VERSION 5.7 ;
  NOWIREEXTENSIONATPIN ON ;
  DIVIDERCHAR "/" ;
  BUSBITCHARS "[]" ;
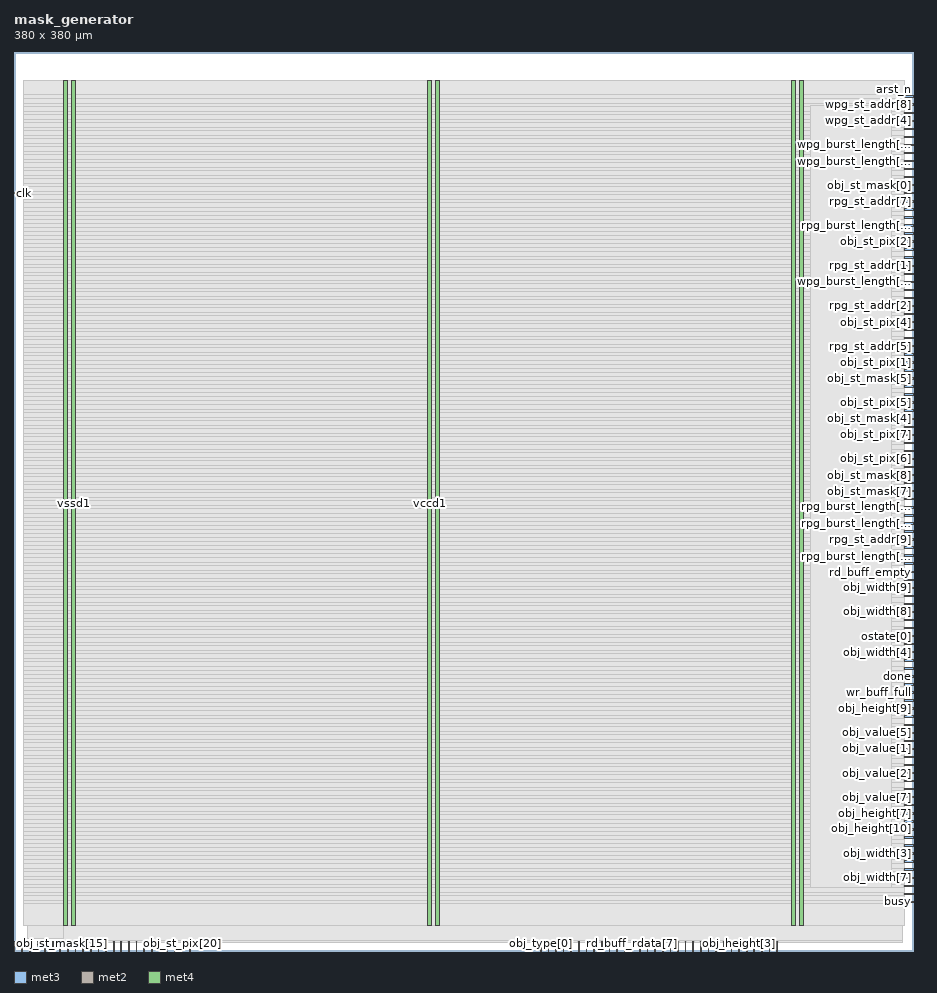
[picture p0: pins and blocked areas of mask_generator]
MACRO mask_generator
  CLASS BLOCK ;
  FOREIGN mask_generator ;
  ORIGIN 0.000 0.000 ;
  SIZE 380.000 BY 380.000 ;
  PIN arst_n
    DIRECTION INPUT ;
    USE SIGNAL ;
    ANTENNAGATEAREA 1.286700 ;
    ANTENNADIFFAREA 0.434700 ;
    PORT
      LAYER met3 ;
        RECT 376.000 360.440 380.000 361.040 ;
    END
  END arst_n
  PIN busy
    DIRECTION OUTPUT ;
    USE SIGNAL ;
    ANTENNADIFFAREA 0.340600 ;
    PORT
      LAYER met3 ;
        RECT 376.000 20.440 380.000 21.040 ;
    END
  END busy
  PIN clk
    DIRECTION INPUT ;
    USE SIGNAL ;
    ANTENNAGATEAREA 1.286700 ;
    ANTENNADIFFAREA 0.434700 ;
    PORT
      LAYER met3 ;
        RECT 0.000 319.640 4.000 320.240 ;
    END
  END clk
  PIN done
    DIRECTION OUTPUT ;
    USE SIGNAL ;
    ANTENNADIFFAREA 0.340600 ;
    PORT
      LAYER met3 ;
        RECT 376.000 115.640 380.000 116.240 ;
    END
  END done
  PIN obj_height[0]
    DIRECTION INPUT ;
    USE SIGNAL ;
    ANTENNAGATEAREA 0.631200 ;
    ANTENNADIFFAREA 0.434700 ;
    PORT
      LAYER met2 ;
        RECT 322.090 0.000 322.370 4.000 ;
    END
  END obj_height[0]
  PIN obj_height[10]
    DIRECTION INPUT ;
    USE SIGNAL ;
    ANTENNAGATEAREA 0.560700 ;
    ANTENNADIFFAREA 0.434700 ;
    PORT
      LAYER met3 ;
        RECT 376.000 54.440 380.000 55.040 ;
    END
  END obj_height[10]
  PIN obj_height[1]
    DIRECTION INPUT ;
    USE SIGNAL ;
    ANTENNAGATEAREA 0.631200 ;
    ANTENNADIFFAREA 0.434700 ;
    PORT
      LAYER met2 ;
        RECT 309.210 0.000 309.490 4.000 ;
    END
  END obj_height[1]
  PIN obj_height[2]
    DIRECTION INPUT ;
    USE SIGNAL ;
    ANTENNAGATEAREA 0.631200 ;
    ANTENNADIFFAREA 0.434700 ;
    PORT
      LAYER met2 ;
        RECT 302.770 0.000 303.050 4.000 ;
    END
  END obj_height[2]
  PIN obj_height[3]
    DIRECTION INPUT ;
    USE SIGNAL ;
    ANTENNAGATEAREA 0.631200 ;
    ANTENNADIFFAREA 0.434700 ;
    PORT
      LAYER met2 ;
        RECT 305.990 0.000 306.270 4.000 ;
    END
  END obj_height[3]
  PIN obj_height[4]
    DIRECTION INPUT ;
    USE SIGNAL ;
    ANTENNAGATEAREA 0.631200 ;
    ANTENNADIFFAREA 0.434700 ;
    PORT
      LAYER met2 ;
        RECT 312.430 0.000 312.710 4.000 ;
    END
  END obj_height[4]
  PIN obj_height[5]
    DIRECTION INPUT ;
    USE SIGNAL ;
    ANTENNAGATEAREA 0.631200 ;
    ANTENNADIFFAREA 0.434700 ;
    PORT
      LAYER met2 ;
        RECT 299.550 0.000 299.830 4.000 ;
    END
  END obj_height[5]
  PIN obj_height[6]
    DIRECTION INPUT ;
    USE SIGNAL ;
    ANTENNAGATEAREA 0.631200 ;
    ANTENNADIFFAREA 0.434700 ;
    PORT
      LAYER met2 ;
        RECT 296.330 0.000 296.610 4.000 ;
    END
  END obj_height[6]
  PIN obj_height[7]
    DIRECTION INPUT ;
    USE SIGNAL ;
    ANTENNAGATEAREA 0.631200 ;
    ANTENNADIFFAREA 0.434700 ;
    PORT
      LAYER met3 ;
        RECT 376.000 57.840 380.000 58.440 ;
    END
  END obj_height[7]
  PIN obj_height[8]
    DIRECTION INPUT ;
    USE SIGNAL ;
    ANTENNAGATEAREA 0.631200 ;
    ANTENNADIFFAREA 0.434700 ;
    PORT
      LAYER met3 ;
        RECT 376.000 61.240 380.000 61.840 ;
    END
  END obj_height[8]
  PIN obj_height[9]
    DIRECTION INPUT ;
    USE SIGNAL ;
    ANTENNAGATEAREA 0.631200 ;
    ANTENNADIFFAREA 0.434700 ;
    PORT
      LAYER met3 ;
        RECT 376.000 102.040 380.000 102.640 ;
    END
  END obj_height[9]
  PIN obj_st_mask[0]
    DIRECTION INPUT ;
    USE SIGNAL ;
    ANTENNAGATEAREA 0.560700 ;
    ANTENNADIFFAREA 0.434700 ;
    PORT
      LAYER met3 ;
        RECT 376.000 323.040 380.000 323.640 ;
    END
  END obj_st_mask[0]
  PIN obj_st_mask[10]
    DIRECTION INPUT ;
    USE SIGNAL ;
    PORT
      LAYER met2 ;
        RECT 0.090 0.000 0.370 4.000 ;
    END
  END obj_st_mask[10]
  PIN obj_st_mask[11]
    DIRECTION INPUT ;
    USE SIGNAL ;
    PORT
      LAYER met2 ;
        RECT 3.310 0.000 3.590 4.000 ;
    END
  END obj_st_mask[11]
  PIN obj_st_mask[12]
    DIRECTION INPUT ;
    USE SIGNAL ;
    PORT
      LAYER met2 ;
        RECT 6.530 0.000 6.810 4.000 ;
    END
  END obj_st_mask[12]
  PIN obj_st_mask[13]
    DIRECTION INPUT ;
    USE SIGNAL ;
    PORT
      LAYER met2 ;
        RECT 9.750 0.000 10.030 4.000 ;
    END
  END obj_st_mask[13]
  PIN obj_st_mask[14]
    DIRECTION INPUT ;
    USE SIGNAL ;
    PORT
      LAYER met2 ;
        RECT 12.970 0.000 13.250 4.000 ;
    END
  END obj_st_mask[14]
  PIN obj_st_mask[15]
    DIRECTION INPUT ;
    USE SIGNAL ;
    PORT
      LAYER met2 ;
        RECT 16.190 0.000 16.470 4.000 ;
    END
  END obj_st_mask[15]
  PIN obj_st_mask[16]
    DIRECTION INPUT ;
    USE SIGNAL ;
    PORT
      LAYER met2 ;
        RECT 19.410 0.000 19.690 4.000 ;
    END
  END obj_st_mask[16]
  PIN obj_st_mask[17]
    DIRECTION INPUT ;
    USE SIGNAL ;
    PORT
      LAYER met2 ;
        RECT 22.630 0.000 22.910 4.000 ;
    END
  END obj_st_mask[17]
  PIN obj_st_mask[18]
    DIRECTION INPUT ;
    USE SIGNAL ;
    PORT
      LAYER met2 ;
        RECT 25.850 0.000 26.130 4.000 ;
    END
  END obj_st_mask[18]
  PIN obj_st_mask[19]
    DIRECTION INPUT ;
    USE SIGNAL ;
    PORT
      LAYER met2 ;
        RECT 29.070 0.000 29.350 4.000 ;
    END
  END obj_st_mask[19]
  PIN obj_st_mask[1]
    DIRECTION INPUT ;
    USE SIGNAL ;
    ANTENNAGATEAREA 0.560700 ;
    ANTENNADIFFAREA 0.434700 ;
    PORT
      LAYER met3 ;
        RECT 376.000 312.840 380.000 313.440 ;
    END
  END obj_st_mask[1]
  PIN obj_st_mask[20]
    DIRECTION INPUT ;
    USE SIGNAL ;
    PORT
      LAYER met2 ;
        RECT 32.290 0.000 32.570 4.000 ;
    END
  END obj_st_mask[20]
  PIN obj_st_mask[21]
    DIRECTION INPUT ;
    USE SIGNAL ;
    PORT
      LAYER met2 ;
        RECT 35.510 0.000 35.790 4.000 ;
    END
  END obj_st_mask[21]
  PIN obj_st_mask[2]
    DIRECTION INPUT ;
    USE SIGNAL ;
    ANTENNAGATEAREA 0.560700 ;
    ANTENNADIFFAREA 0.434700 ;
    PORT
      LAYER met3 ;
        RECT 376.000 278.840 380.000 279.440 ;
    END
  END obj_st_mask[2]
  PIN obj_st_mask[3]
    DIRECTION INPUT ;
    USE SIGNAL ;
    ANTENNAGATEAREA 0.560700 ;
    ANTENNADIFFAREA 0.434700 ;
    PORT
      LAYER met3 ;
        RECT 376.000 302.640 380.000 303.240 ;
    END
  END obj_st_mask[3]
  PIN obj_st_mask[4]
    DIRECTION INPUT ;
    USE SIGNAL ;
    ANTENNAGATEAREA 0.560700 ;
    ANTENNADIFFAREA 0.434700 ;
    PORT
      LAYER met3 ;
        RECT 376.000 224.440 380.000 225.040 ;
    END
  END obj_st_mask[4]
  PIN obj_st_mask[5]
    DIRECTION INPUT ;
    USE SIGNAL ;
    ANTENNAGATEAREA 0.560700 ;
    ANTENNADIFFAREA 0.434700 ;
    PORT
      LAYER met3 ;
        RECT 376.000 241.440 380.000 242.040 ;
    END
  END obj_st_mask[5]
  PIN obj_st_mask[6]
    DIRECTION INPUT ;
    USE SIGNAL ;
    ANTENNAGATEAREA 0.560700 ;
    ANTENNADIFFAREA 0.434700 ;
    PORT
      LAYER met3 ;
        RECT 376.000 217.640 380.000 218.240 ;
    END
  END obj_st_mask[6]
  PIN obj_st_mask[7]
    DIRECTION INPUT ;
    USE SIGNAL ;
    ANTENNAGATEAREA 0.560700 ;
    ANTENNADIFFAREA 0.434700 ;
    PORT
      LAYER met3 ;
        RECT 376.000 193.840 380.000 194.440 ;
    END
  END obj_st_mask[7]
  PIN obj_st_mask[8]
    DIRECTION INPUT ;
    USE SIGNAL ;
    ANTENNAGATEAREA 0.560700 ;
    ANTENNADIFFAREA 0.434700 ;
    PORT
      LAYER met3 ;
        RECT 376.000 197.240 380.000 197.840 ;
    END
  END obj_st_mask[8]
  PIN obj_st_mask[9]
    DIRECTION INPUT ;
    USE SIGNAL ;
    ANTENNAGATEAREA 0.560700 ;
    ANTENNADIFFAREA 0.434700 ;
    PORT
      LAYER met3 ;
        RECT 376.000 183.640 380.000 184.240 ;
    END
  END obj_st_mask[9]
  PIN obj_st_pix[0]
    DIRECTION INPUT ;
    USE SIGNAL ;
    ANTENNAGATEAREA 0.560700 ;
    ANTENNADIFFAREA 0.434700 ;
    PORT
      LAYER met3 ;
        RECT 376.000 295.840 380.000 296.440 ;
    END
  END obj_st_pix[0]
  PIN obj_st_pix[10]
    DIRECTION INPUT ;
    USE SIGNAL ;
    PORT
      LAYER met2 ;
        RECT 38.730 0.000 39.010 4.000 ;
    END
  END obj_st_pix[10]
  PIN obj_st_pix[11]
    DIRECTION INPUT ;
    USE SIGNAL ;
    PORT
      LAYER met2 ;
        RECT 41.950 0.000 42.230 4.000 ;
    END
  END obj_st_pix[11]
  PIN obj_st_pix[12]
    DIRECTION INPUT ;
    USE SIGNAL ;
    PORT
      LAYER met2 ;
        RECT 45.170 0.000 45.450 4.000 ;
    END
  END obj_st_pix[12]
  PIN obj_st_pix[13]
    DIRECTION INPUT ;
    USE SIGNAL ;
    PORT
      LAYER met2 ;
        RECT 48.390 0.000 48.670 4.000 ;
    END
  END obj_st_pix[13]
  PIN obj_st_pix[14]
    DIRECTION INPUT ;
    USE SIGNAL ;
    PORT
      LAYER met2 ;
        RECT 51.610 0.000 51.890 4.000 ;
    END
  END obj_st_pix[14]
  PIN obj_st_pix[15]
    DIRECTION INPUT ;
    USE SIGNAL ;
    PORT
      LAYER met2 ;
        RECT 54.830 0.000 55.110 4.000 ;
    END
  END obj_st_pix[15]
  PIN obj_st_pix[16]
    DIRECTION INPUT ;
    USE SIGNAL ;
    PORT
      LAYER met2 ;
        RECT 58.050 0.000 58.330 4.000 ;
    END
  END obj_st_pix[16]
  PIN obj_st_pix[17]
    DIRECTION INPUT ;
    USE SIGNAL ;
    PORT
      LAYER met2 ;
        RECT 61.270 0.000 61.550 4.000 ;
    END
  END obj_st_pix[17]
  PIN obj_st_pix[18]
    DIRECTION INPUT ;
    USE SIGNAL ;
    PORT
      LAYER met2 ;
        RECT 64.490 0.000 64.770 4.000 ;
    END
  END obj_st_pix[18]
  PIN obj_st_pix[19]
    DIRECTION INPUT ;
    USE SIGNAL ;
    PORT
      LAYER met2 ;
        RECT 67.710 0.000 67.990 4.000 ;
    END
  END obj_st_pix[19]
  PIN obj_st_pix[1]
    DIRECTION INPUT ;
    USE SIGNAL ;
    ANTENNAGATEAREA 0.560700 ;
    ANTENNADIFFAREA 0.434700 ;
    PORT
      LAYER met3 ;
        RECT 376.000 248.240 380.000 248.840 ;
    END
  END obj_st_pix[1]
  PIN obj_st_pix[20]
    DIRECTION INPUT ;
    USE SIGNAL ;
    PORT
      LAYER met2 ;
        RECT 70.930 0.000 71.210 4.000 ;
    END
  END obj_st_pix[20]
  PIN obj_st_pix[21]
    DIRECTION INPUT ;
    USE SIGNAL ;
    PORT
      LAYER met2 ;
        RECT 74.150 0.000 74.430 4.000 ;
    END
  END obj_st_pix[21]
  PIN obj_st_pix[2]
    DIRECTION INPUT ;
    USE SIGNAL ;
    ANTENNAGATEAREA 0.560700 ;
    ANTENNADIFFAREA 0.434700 ;
    PORT
      LAYER met3 ;
        RECT 376.000 299.240 380.000 299.840 ;
    END
  END obj_st_pix[2]
  PIN obj_st_pix[3]
    DIRECTION INPUT ;
    USE SIGNAL ;
    ANTENNAGATEAREA 0.560700 ;
    ANTENNADIFFAREA 0.434700 ;
    PORT
      LAYER met3 ;
        RECT 376.000 244.840 380.000 245.440 ;
    END
  END obj_st_pix[3]
  PIN obj_st_pix[4]
    DIRECTION INPUT ;
    USE SIGNAL ;
    ANTENNAGATEAREA 0.560700 ;
    ANTENNADIFFAREA 0.434700 ;
    PORT
      LAYER met3 ;
        RECT 376.000 265.240 380.000 265.840 ;
    END
  END obj_st_pix[4]
  PIN obj_st_pix[5]
    DIRECTION INPUT ;
    USE SIGNAL ;
    ANTENNAGATEAREA 0.560700 ;
    ANTENNADIFFAREA 0.434700 ;
    PORT
      LAYER met3 ;
        RECT 376.000 231.240 380.000 231.840 ;
    END
  END obj_st_pix[5]
  PIN obj_st_pix[6]
    DIRECTION INPUT ;
    USE SIGNAL ;
    ANTENNAGATEAREA 0.560700 ;
    ANTENNADIFFAREA 0.434700 ;
    PORT
      LAYER met3 ;
        RECT 376.000 207.440 380.000 208.040 ;
    END
  END obj_st_pix[6]
  PIN obj_st_pix[7]
    DIRECTION INPUT ;
    USE SIGNAL ;
    ANTENNAGATEAREA 0.560700 ;
    ANTENNADIFFAREA 0.434700 ;
    PORT
      LAYER met3 ;
        RECT 376.000 221.040 380.000 221.640 ;
    END
  END obj_st_pix[7]
  PIN obj_st_pix[8]
    DIRECTION INPUT ;
    USE SIGNAL ;
    ANTENNAGATEAREA 0.560700 ;
    ANTENNADIFFAREA 0.434700 ;
    PORT
      LAYER met3 ;
        RECT 376.000 200.640 380.000 201.240 ;
    END
  END obj_st_pix[8]
  PIN obj_st_pix[9]
    DIRECTION INPUT ;
    USE SIGNAL ;
    ANTENNAGATEAREA 0.647700 ;
    ANTENNADIFFAREA 0.434700 ;
    PORT
      LAYER met3 ;
        RECT 376.000 23.840 380.000 24.440 ;
    END
  END obj_st_pix[9]
  PIN obj_type[0]
    DIRECTION INPUT ;
    USE SIGNAL ;
    ANTENNAGATEAREA 0.631200 ;
    ANTENNADIFFAREA 0.434700 ;
    PORT
      LAYER met2 ;
        RECT 222.270 0.000 222.550 4.000 ;
    END
  END obj_type[0]
  PIN obj_type[1]
    DIRECTION INPUT ;
    USE SIGNAL ;
    ANTENNAGATEAREA 0.631200 ;
    ANTENNADIFFAREA 0.434700 ;
    PORT
      LAYER met2 ;
        RECT 225.490 0.000 225.770 4.000 ;
    END
  END obj_type[1]
  PIN obj_type[2]
    DIRECTION INPUT ;
    USE SIGNAL ;
    ANTENNAGATEAREA 0.631200 ;
    ANTENNADIFFAREA 0.434700 ;
    PORT
      LAYER met2 ;
        RECT 254.470 0.000 254.750 4.000 ;
    END
  END obj_type[2]
  PIN obj_type[3]
    DIRECTION INPUT ;
    USE SIGNAL ;
    ANTENNAGATEAREA 0.631200 ;
    ANTENNADIFFAREA 0.434700 ;
    PORT
      LAYER met2 ;
        RECT 257.690 0.000 257.970 4.000 ;
    END
  END obj_type[3]
  PIN obj_value[0]
    DIRECTION INPUT ;
    USE SIGNAL ;
    ANTENNAGATEAREA 0.631200 ;
    ANTENNADIFFAREA 0.434700 ;
    PORT
      LAYER met3 ;
        RECT 376.000 71.440 380.000 72.040 ;
    END
  END obj_value[0]
  PIN obj_value[10]
    DIRECTION INPUT ;
    USE SIGNAL ;
    ANTENNAGATEAREA 0.631200 ;
    ANTENNADIFFAREA 0.434700 ;
    PORT
      LAYER met2 ;
        RECT 293.110 0.000 293.390 4.000 ;
    END
  END obj_value[10]
  PIN obj_value[11]
    DIRECTION INPUT ;
    USE SIGNAL ;
    ANTENNAGATEAREA 0.631200 ;
    ANTENNADIFFAREA 0.434700 ;
    PORT
      LAYER met2 ;
        RECT 277.010 0.000 277.290 4.000 ;
    END
  END obj_value[11]
  PIN obj_value[12]
    DIRECTION INPUT ;
    USE SIGNAL ;
    ANTENNAGATEAREA 0.631200 ;
    ANTENNADIFFAREA 0.434700 ;
    PORT
      LAYER met2 ;
        RECT 286.670 0.000 286.950 4.000 ;
    END
  END obj_value[12]
  PIN obj_value[13]
    DIRECTION INPUT ;
    USE SIGNAL ;
    ANTENNAGATEAREA 0.631200 ;
    ANTENNADIFFAREA 0.434700 ;
    PORT
      LAYER met2 ;
        RECT 280.230 0.000 280.510 4.000 ;
    END
  END obj_value[13]
  PIN obj_value[14]
    DIRECTION INPUT ;
    USE SIGNAL ;
    ANTENNAGATEAREA 0.631200 ;
    ANTENNADIFFAREA 0.434700 ;
    PORT
      LAYER met2 ;
        RECT 289.890 0.000 290.170 4.000 ;
    END
  END obj_value[14]
  PIN obj_value[1]
    DIRECTION INPUT ;
    USE SIGNAL ;
    ANTENNAGATEAREA 0.631200 ;
    ANTENNADIFFAREA 0.434700 ;
    PORT
      LAYER met3 ;
        RECT 376.000 85.040 380.000 85.640 ;
    END
  END obj_value[1]
  PIN obj_value[2]
    DIRECTION INPUT ;
    USE SIGNAL ;
    ANTENNAGATEAREA 0.631200 ;
    ANTENNADIFFAREA 0.434700 ;
    PORT
      LAYER met3 ;
        RECT 376.000 74.840 380.000 75.440 ;
    END
  END obj_value[2]
  PIN obj_value[3]
    DIRECTION INPUT ;
    USE SIGNAL ;
    ANTENNAGATEAREA 0.631200 ;
    ANTENNADIFFAREA 0.434700 ;
    PORT
      LAYER met3 ;
        RECT 376.000 78.240 380.000 78.840 ;
    END
  END obj_value[3]
  PIN obj_value[4]
    DIRECTION INPUT ;
    USE SIGNAL ;
    ANTENNAGATEAREA 0.631200 ;
    ANTENNADIFFAREA 0.434700 ;
    PORT
      LAYER met3 ;
        RECT 376.000 88.440 380.000 89.040 ;
    END
  END obj_value[4]
  PIN obj_value[5]
    DIRECTION INPUT ;
    USE SIGNAL ;
    ANTENNAGATEAREA 0.631200 ;
    ANTENNADIFFAREA 0.434700 ;
    PORT
      LAYER met3 ;
        RECT 376.000 91.840 380.000 92.440 ;
    END
  END obj_value[5]
  PIN obj_value[6]
    DIRECTION INPUT ;
    USE SIGNAL ;
    ANTENNAGATEAREA 0.631200 ;
    ANTENNADIFFAREA 0.434700 ;
    PORT
      LAYER met3 ;
        RECT 376.000 95.240 380.000 95.840 ;
    END
  END obj_value[6]
  PIN obj_value[7]
    DIRECTION INPUT ;
    USE SIGNAL ;
    ANTENNAGATEAREA 0.631200 ;
    ANTENNADIFFAREA 0.434700 ;
    PORT
      LAYER met3 ;
        RECT 376.000 64.640 380.000 65.240 ;
    END
  END obj_value[7]
  PIN obj_value[8]
    DIRECTION INPUT ;
    USE SIGNAL ;
    ANTENNAGATEAREA 0.631200 ;
    ANTENNADIFFAREA 0.434700 ;
    PORT
      LAYER met3 ;
        RECT 376.000 98.640 380.000 99.240 ;
    END
  END obj_value[8]
  PIN obj_value[9]
    DIRECTION INPUT ;
    USE SIGNAL ;
    ANTENNAGATEAREA 0.560700 ;
    ANTENNADIFFAREA 0.434700 ;
    PORT
      LAYER met3 ;
        RECT 376.000 81.640 380.000 82.240 ;
    END
  END obj_value[9]
  PIN obj_width[0]
    DIRECTION INPUT ;
    USE SIGNAL ;
    ANTENNAGATEAREA 0.560700 ;
    ANTENNADIFFAREA 0.434700 ;
    PORT
      LAYER met3 ;
        RECT 376.000 105.440 380.000 106.040 ;
    END
  END obj_width[0]
  PIN obj_width[10]
    DIRECTION INPUT ;
    USE SIGNAL ;
    ANTENNAGATEAREA 0.631200 ;
    ANTENNADIFFAREA 0.434700 ;
    PORT
      LAYER met3 ;
        RECT 376.000 27.240 380.000 27.840 ;
    END
  END obj_width[10]
  PIN obj_width[1]
    DIRECTION INPUT ;
    USE SIGNAL ;
    ANTENNAGATEAREA 0.560700 ;
    ANTENNADIFFAREA 0.434700 ;
    PORT
      LAYER met3 ;
        RECT 376.000 112.240 380.000 112.840 ;
    END
  END obj_width[1]
  PIN obj_width[2]
    DIRECTION INPUT ;
    USE SIGNAL ;
    ANTENNAGATEAREA 0.560700 ;
    ANTENNADIFFAREA 0.434700 ;
    PORT
      LAYER met3 ;
        RECT 376.000 34.040 380.000 34.640 ;
    END
  END obj_width[2]
  PIN obj_width[3]
    DIRECTION INPUT ;
    USE SIGNAL ;
    ANTENNAGATEAREA 0.560700 ;
    ANTENNADIFFAREA 0.434700 ;
    PORT
      LAYER met3 ;
        RECT 376.000 40.840 380.000 41.440 ;
    END
  END obj_width[3]
  PIN obj_width[4]
    DIRECTION INPUT ;
    USE SIGNAL ;
    ANTENNAGATEAREA 0.560700 ;
    ANTENNADIFFAREA 0.434700 ;
    PORT
      LAYER met3 ;
        RECT 376.000 125.840 380.000 126.440 ;
    END
  END obj_width[4]
  PIN obj_width[5]
    DIRECTION INPUT ;
    USE SIGNAL ;
    ANTENNAGATEAREA 0.560700 ;
    ANTENNADIFFAREA 0.434700 ;
    PORT
      LAYER met3 ;
        RECT 376.000 51.040 380.000 51.640 ;
    END
  END obj_width[5]
  PIN obj_width[6]
    DIRECTION INPUT ;
    USE SIGNAL ;
    ANTENNAGATEAREA 0.560700 ;
    ANTENNADIFFAREA 0.434700 ;
    PORT
      LAYER met3 ;
        RECT 376.000 37.440 380.000 38.040 ;
    END
  END obj_width[6]
  PIN obj_width[7]
    DIRECTION INPUT ;
    USE SIGNAL ;
    ANTENNAGATEAREA 0.560700 ;
    ANTENNADIFFAREA 0.434700 ;
    PORT
      LAYER met3 ;
        RECT 376.000 30.640 380.000 31.240 ;
    END
  END obj_width[7]
  PIN obj_width[8]
    DIRECTION INPUT ;
    USE SIGNAL ;
    ANTENNAGATEAREA 0.560700 ;
    ANTENNADIFFAREA 0.434700 ;
    PORT
      LAYER met3 ;
        RECT 376.000 142.840 380.000 143.440 ;
    END
  END obj_width[8]
  PIN obj_width[9]
    DIRECTION INPUT ;
    USE SIGNAL ;
    ANTENNAGATEAREA 0.560700 ;
    ANTENNADIFFAREA 0.434700 ;
    PORT
      LAYER met3 ;
        RECT 376.000 153.040 380.000 153.640 ;
    END
  END obj_width[9]
  PIN ostate[0]
    DIRECTION OUTPUT ;
    USE SIGNAL ;
    ANTENNADIFFAREA 0.340600 ;
    PORT
      LAYER met3 ;
        RECT 376.000 129.240 380.000 129.840 ;
    END
  END ostate[0]
  PIN ostate[1]
    DIRECTION OUTPUT ;
    USE SIGNAL ;
    ANTENNADIFFAREA 0.340600 ;
    PORT
      LAYER met3 ;
        RECT 376.000 68.040 380.000 68.640 ;
    END
  END ostate[1]
  PIN ostate[2]
    DIRECTION OUTPUT ;
    USE SIGNAL ;
    ANTENNADIFFAREA 0.340600 ;
    PORT
      LAYER met3 ;
        RECT 376.000 136.040 380.000 136.640 ;
    END
  END ostate[2]
  PIN ostate[3]
    DIRECTION OUTPUT ;
    USE SIGNAL ;
    ANTENNADIFFAREA 0.340600 ;
    PORT
      LAYER met3 ;
        RECT 376.000 132.640 380.000 133.240 ;
    END
  END ostate[3]
  PIN rd_buff_empty
    DIRECTION INPUT ;
    USE SIGNAL ;
    ANTENNAGATEAREA 0.631200 ;
    ANTENNADIFFAREA 0.434700 ;
    PORT
      LAYER met3 ;
        RECT 376.000 156.440 380.000 157.040 ;
    END
  END rd_buff_empty
  PIN rd_buff_rdata[0]
    DIRECTION INPUT ;
    USE SIGNAL ;
    ANTENNAGATEAREA 0.560700 ;
    ANTENNADIFFAREA 0.434700 ;
    PORT
      LAYER met2 ;
        RECT 228.710 0.000 228.990 4.000 ;
    END
  END rd_buff_rdata[0]
  PIN rd_buff_rdata[1]
    DIRECTION INPUT ;
    USE SIGNAL ;
    ANTENNAGATEAREA 0.560700 ;
    ANTENNADIFFAREA 0.434700 ;
    PORT
      LAYER met2 ;
        RECT 231.930 0.000 232.210 4.000 ;
    END
  END rd_buff_rdata[1]
  PIN rd_buff_rdata[2]
    DIRECTION INPUT ;
    USE SIGNAL ;
    ANTENNAGATEAREA 0.560700 ;
    ANTENNADIFFAREA 0.434700 ;
    PORT
      LAYER met2 ;
        RECT 251.250 0.000 251.530 4.000 ;
    END
  END rd_buff_rdata[2]
  PIN rd_buff_rdata[3]
    DIRECTION INPUT ;
    USE SIGNAL ;
    ANTENNAGATEAREA 0.560700 ;
    ANTENNADIFFAREA 0.434700 ;
    PORT
      LAYER met2 ;
        RECT 318.870 0.000 319.150 4.000 ;
    END
  END rd_buff_rdata[3]
  PIN rd_buff_rdata[4]
    DIRECTION INPUT ;
    USE SIGNAL ;
    ANTENNAGATEAREA 0.560700 ;
    ANTENNADIFFAREA 0.434700 ;
    PORT
      LAYER met2 ;
        RECT 270.570 0.000 270.850 4.000 ;
    END
  END rd_buff_rdata[4]
  PIN rd_buff_rdata[5]
    DIRECTION INPUT ;
    USE SIGNAL ;
    ANTENNAGATEAREA 0.560700 ;
    ANTENNADIFFAREA 0.434700 ;
    PORT
      LAYER met2 ;
        RECT 235.150 0.000 235.430 4.000 ;
    END
  END rd_buff_rdata[5]
  PIN rd_buff_rdata[6]
    DIRECTION INPUT ;
    USE SIGNAL ;
    ANTENNAGATEAREA 0.560700 ;
    ANTENNADIFFAREA 0.434700 ;
    PORT
      LAYER met2 ;
        RECT 315.650 0.000 315.930 4.000 ;
    END
  END rd_buff_rdata[6]
  PIN rd_buff_rdata[7]
    DIRECTION INPUT ;
    USE SIGNAL ;
    ANTENNAGATEAREA 0.631200 ;
    ANTENNADIFFAREA 0.434700 ;
    PORT
      LAYER met2 ;
        RECT 260.910 0.000 261.190 4.000 ;
    END
  END rd_buff_rdata[7]
  PIN rd_buff_rden
    DIRECTION OUTPUT ;
    USE SIGNAL ;
    ANTENNADIFFAREA 0.340600 ;
    PORT
      LAYER met3 ;
        RECT 376.000 119.040 380.000 119.640 ;
    END
  END rd_buff_rden
  PIN rpg_ack
    DIRECTION INPUT ;
    USE SIGNAL ;
    ANTENNAGATEAREA 0.560700 ;
    ANTENNADIFFAREA 0.434700 ;
    PORT
      LAYER met3 ;
        RECT 376.000 146.240 380.000 146.840 ;
    END
  END rpg_ack
  PIN rpg_burst_length[0]
    DIRECTION OUTPUT ;
    USE SIGNAL ;
    ANTENNADIFFAREA 0.340600 ;
    PORT
      LAYER met3 ;
        RECT 376.000 346.840 380.000 347.440 ;
    END
  END rpg_burst_length[0]
  PIN rpg_burst_length[1]
    DIRECTION OUTPUT ;
    USE SIGNAL ;
    ANTENNADIFFAREA 0.340600 ;
    PORT
      LAYER met3 ;
        RECT 376.000 306.040 380.000 306.640 ;
    END
  END rpg_burst_length[1]
  PIN rpg_burst_length[2]
    DIRECTION OUTPUT ;
    USE SIGNAL ;
    ANTENNADIFFAREA 0.340600 ;
    PORT
      LAYER met3 ;
        RECT 376.000 258.440 380.000 259.040 ;
    END
  END rpg_burst_length[2]
  PIN rpg_burst_length[3]
    DIRECTION OUTPUT ;
    USE SIGNAL ;
    ANTENNADIFFAREA 0.340600 ;
    PORT
      LAYER met3 ;
        RECT 376.000 292.440 380.000 293.040 ;
    END
  END rpg_burst_length[3]
  PIN rpg_burst_length[4]
    DIRECTION OUTPUT ;
    USE SIGNAL ;
    ANTENNADIFFAREA 0.340600 ;
    PORT
      LAYER met3 ;
        RECT 376.000 353.640 380.000 354.240 ;
    END
  END rpg_burst_length[4]
  PIN rpg_burst_length[5]
    DIRECTION OUTPUT ;
    USE SIGNAL ;
    ANTENNADIFFAREA 0.340600 ;
    PORT
      LAYER met3 ;
        RECT 376.000 261.840 380.000 262.440 ;
    END
  END rpg_burst_length[5]
  PIN rpg_burst_length[6]
    DIRECTION OUTPUT ;
    USE SIGNAL ;
    ANTENNADIFFAREA 0.340600 ;
    PORT
      LAYER met3 ;
        RECT 376.000 190.440 380.000 191.040 ;
    END
  END rpg_burst_length[6]
  PIN rpg_burst_length[7]
    DIRECTION OUTPUT ;
    USE SIGNAL ;
    ANTENNADIFFAREA 0.340600 ;
    PORT
      LAYER met3 ;
        RECT 376.000 180.240 380.000 180.840 ;
    END
  END rpg_burst_length[7]
  PIN rpg_burst_length[8]
    DIRECTION OUTPUT ;
    USE SIGNAL ;
    ANTENNADIFFAREA 0.340600 ;
    PORT
      LAYER met3 ;
        RECT 376.000 163.240 380.000 163.840 ;
    END
  END rpg_burst_length[8]
  PIN rpg_burst_length[9]
    DIRECTION OUTPUT ;
    USE SIGNAL ;
    ANTENNADIFFAREA 0.340600 ;
    PORT
      LAYER met3 ;
        RECT 376.000 166.640 380.000 167.240 ;
    END
  END rpg_burst_length[9]
  PIN rpg_busy
    DIRECTION OUTPUT ;
    USE SIGNAL ;
    ANTENNADIFFAREA 0.340600 ;
    PORT
      LAYER met3 ;
        RECT 376.000 139.440 380.000 140.040 ;
    END
  END rpg_busy
  PIN rpg_st_addr[0]
    DIRECTION OUTPUT ;
    USE SIGNAL ;
    ANTENNADIFFAREA 0.340600 ;
    PORT
      LAYER met3 ;
        RECT 376.000 275.440 380.000 276.040 ;
    END
  END rpg_st_addr[0]
  PIN rpg_st_addr[1]
    DIRECTION OUTPUT ;
    USE SIGNAL ;
    ANTENNADIFFAREA 0.340600 ;
    PORT
      LAYER met3 ;
        RECT 376.000 289.040 380.000 289.640 ;
    END
  END rpg_st_addr[1]
  PIN rpg_st_addr[2]
    DIRECTION OUTPUT ;
    USE SIGNAL ;
    ANTENNADIFFAREA 0.340600 ;
    PORT
      LAYER met3 ;
        RECT 376.000 272.040 380.000 272.640 ;
    END
  END rpg_st_addr[2]
  PIN rpg_st_addr[3]
    DIRECTION OUTPUT ;
    USE SIGNAL ;
    ANTENNADIFFAREA 0.340600 ;
    PORT
      LAYER met3 ;
        RECT 376.000 326.440 380.000 327.040 ;
    END
  END rpg_st_addr[3]
  PIN rpg_st_addr[4]
    DIRECTION OUTPUT ;
    USE SIGNAL ;
    ANTENNADIFFAREA 0.340600 ;
    PORT
      LAYER met3 ;
        RECT 376.000 238.040 380.000 238.640 ;
    END
  END rpg_st_addr[4]
  PIN rpg_st_addr[5]
    DIRECTION OUTPUT ;
    USE SIGNAL ;
    ANTENNADIFFAREA 0.340600 ;
    PORT
      LAYER met3 ;
        RECT 376.000 255.040 380.000 255.640 ;
    END
  END rpg_st_addr[5]
  PIN rpg_st_addr[6]
    DIRECTION OUTPUT ;
    USE SIGNAL ;
    ANTENNADIFFAREA 0.340600 ;
    PORT
      LAYER met3 ;
        RECT 376.000 343.440 380.000 344.040 ;
    END
  END rpg_st_addr[6]
  PIN rpg_st_addr[7]
    DIRECTION OUTPUT ;
    USE SIGNAL ;
    ANTENNADIFFAREA 0.340600 ;
    PORT
      LAYER met3 ;
        RECT 376.000 316.240 380.000 316.840 ;
    END
  END rpg_st_addr[7]
  PIN rpg_st_addr[8]
    DIRECTION OUTPUT ;
    USE SIGNAL ;
    ANTENNADIFFAREA 0.340600 ;
    PORT
      LAYER met3 ;
        RECT 376.000 234.640 380.000 235.240 ;
    END
  END rpg_st_addr[8]
  PIN rpg_st_addr[9]
    DIRECTION OUTPUT ;
    USE SIGNAL ;
    ANTENNADIFFAREA 0.340600 ;
    PORT
      LAYER met3 ;
        RECT 376.000 173.440 380.000 174.040 ;
    END
  END rpg_st_addr[9]
  PIN start
    DIRECTION INPUT ;
    USE SIGNAL ;
    ANTENNAGATEAREA 0.593700 ;
    ANTENNADIFFAREA 0.434700 ;
    PORT
      LAYER met3 ;
        RECT 376.000 159.840 380.000 160.440 ;
    END
  END start
  PIN vccd1
    DIRECTION INOUT ;
    USE POWER ;
    PORT
      LAYER met4 ;
        RECT 21.040 10.640 22.640 367.440 ;
    END
    PORT
      LAYER met4 ;
        RECT 174.640 10.640 176.240 367.440 ;
    END
    PORT
      LAYER met4 ;
        RECT 328.240 10.640 329.840 367.440 ;
    END
  END vccd1
  PIN vssd1
    DIRECTION INOUT ;
    USE GROUND ;
    PORT
      LAYER met4 ;
        RECT 24.340 10.640 25.940 367.440 ;
    END
    PORT
      LAYER met4 ;
        RECT 177.940 10.640 179.540 367.440 ;
    END
    PORT
      LAYER met4 ;
        RECT 331.540 10.640 333.140 367.440 ;
    END
  END vssd1
  PIN wpg_ack
    DIRECTION INPUT ;
    USE SIGNAL ;
    ANTENNAGATEAREA 0.560700 ;
    ANTENNADIFFAREA 0.434700 ;
    PORT
      LAYER met3 ;
        RECT 376.000 44.240 380.000 44.840 ;
    END
  END wpg_ack
  PIN wpg_burst_length[0]
    DIRECTION OUTPUT ;
    USE SIGNAL ;
    ANTENNADIFFAREA 0.340600 ;
    PORT
      LAYER met3 ;
        RECT 376.000 333.240 380.000 333.840 ;
    END
  END wpg_burst_length[0]
  PIN wpg_burst_length[1]
    DIRECTION OUTPUT ;
    USE SIGNAL ;
    ANTENNADIFFAREA 0.340600 ;
    PORT
      LAYER met3 ;
        RECT 376.000 319.640 380.000 320.240 ;
    END
  END wpg_burst_length[1]
  PIN wpg_burst_length[2]
    DIRECTION OUTPUT ;
    USE SIGNAL ;
    ANTENNADIFFAREA 0.340600 ;
    PORT
      LAYER met3 ;
        RECT 376.000 282.240 380.000 282.840 ;
    END
  END wpg_burst_length[2]
  PIN wpg_burst_length[3]
    DIRECTION OUTPUT ;
    USE SIGNAL ;
    ANTENNADIFFAREA 0.340600 ;
    PORT
      LAYER met3 ;
        RECT 376.000 309.440 380.000 310.040 ;
    END
  END wpg_burst_length[3]
  PIN wpg_burst_length[4]
    DIRECTION OUTPUT ;
    USE SIGNAL ;
    ANTENNADIFFAREA 0.340600 ;
    PORT
      LAYER met3 ;
        RECT 376.000 227.840 380.000 228.440 ;
    END
  END wpg_burst_length[4]
  PIN wpg_burst_length[5]
    DIRECTION OUTPUT ;
    USE SIGNAL ;
    ANTENNADIFFAREA 0.340600 ;
    PORT
      LAYER met3 ;
        RECT 376.000 340.040 380.000 340.640 ;
    END
  END wpg_burst_length[5]
  PIN wpg_burst_length[6]
    DIRECTION OUTPUT ;
    USE SIGNAL ;
    ANTENNADIFFAREA 0.340600 ;
    PORT
      LAYER met3 ;
        RECT 376.000 210.840 380.000 211.440 ;
    END
  END wpg_burst_length[6]
  PIN wpg_burst_length[7]
    DIRECTION OUTPUT ;
    USE SIGNAL ;
    ANTENNADIFFAREA 0.340600 ;
    PORT
      LAYER met3 ;
        RECT 376.000 187.040 380.000 187.640 ;
    END
  END wpg_burst_length[7]
  PIN wpg_burst_length[8]
    DIRECTION OUTPUT ;
    USE SIGNAL ;
    ANTENNADIFFAREA 0.340600 ;
    PORT
      LAYER met3 ;
        RECT 376.000 149.640 380.000 150.240 ;
    END
  END wpg_burst_length[8]
  PIN wpg_burst_length[9]
    DIRECTION OUTPUT ;
    USE SIGNAL ;
    ANTENNADIFFAREA 0.340600 ;
    PORT
      LAYER met3 ;
        RECT 376.000 170.040 380.000 170.640 ;
    END
  END wpg_burst_length[9]
  PIN wpg_busy
    DIRECTION OUTPUT ;
    USE SIGNAL ;
    ANTENNADIFFAREA 0.340600 ;
    PORT
      LAYER met3 ;
        RECT 376.000 47.640 380.000 48.240 ;
    END
  END wpg_busy
  PIN wpg_st_addr[0]
    DIRECTION OUTPUT ;
    USE SIGNAL ;
    ANTENNADIFFAREA 0.340600 ;
    PORT
      LAYER met3 ;
        RECT 376.000 251.640 380.000 252.240 ;
    END
  END wpg_st_addr[0]
  PIN wpg_st_addr[1]
    DIRECTION OUTPUT ;
    USE SIGNAL ;
    ANTENNADIFFAREA 0.340600 ;
    PORT
      LAYER met3 ;
        RECT 376.000 285.640 380.000 286.240 ;
    END
  END wpg_st_addr[1]
  PIN wpg_st_addr[2]
    DIRECTION OUTPUT ;
    USE SIGNAL ;
    ANTENNADIFFAREA 0.340600 ;
    PORT
      LAYER met3 ;
        RECT 376.000 329.840 380.000 330.440 ;
    END
  END wpg_st_addr[2]
  PIN wpg_st_addr[3]
    DIRECTION OUTPUT ;
    USE SIGNAL ;
    ANTENNADIFFAREA 0.340600 ;
    PORT
      LAYER met3 ;
        RECT 376.000 268.640 380.000 269.240 ;
    END
  END wpg_st_addr[3]
  PIN wpg_st_addr[4]
    DIRECTION OUTPUT ;
    USE SIGNAL ;
    ANTENNADIFFAREA 0.340600 ;
    PORT
      LAYER met3 ;
        RECT 376.000 350.240 380.000 350.840 ;
    END
  END wpg_st_addr[4]
  PIN wpg_st_addr[5]
    DIRECTION OUTPUT ;
    USE SIGNAL ;
    ANTENNADIFFAREA 0.340600 ;
    PORT
      LAYER met3 ;
        RECT 376.000 336.640 380.000 337.240 ;
    END
  END wpg_st_addr[5]
  PIN wpg_st_addr[6]
    DIRECTION OUTPUT ;
    USE SIGNAL ;
    ANTENNADIFFAREA 0.340600 ;
    PORT
      LAYER met3 ;
        RECT 376.000 214.240 380.000 214.840 ;
    END
  END wpg_st_addr[6]
  PIN wpg_st_addr[7]
    DIRECTION OUTPUT ;
    USE SIGNAL ;
    ANTENNADIFFAREA 0.340600 ;
    PORT
      LAYER met3 ;
        RECT 376.000 204.040 380.000 204.640 ;
    END
  END wpg_st_addr[7]
  PIN wpg_st_addr[8]
    DIRECTION OUTPUT ;
    USE SIGNAL ;
    ANTENNADIFFAREA 0.340600 ;
    PORT
      LAYER met3 ;
        RECT 376.000 357.040 380.000 357.640 ;
    END
  END wpg_st_addr[8]
  PIN wpg_st_addr[9]
    DIRECTION OUTPUT ;
    USE SIGNAL ;
    ANTENNADIFFAREA 0.340600 ;
    PORT
      LAYER met3 ;
        RECT 376.000 176.840 380.000 177.440 ;
    END
  END wpg_st_addr[9]
  PIN wr_buff_full
    DIRECTION INPUT ;
    USE SIGNAL ;
    ANTENNAGATEAREA 0.631200 ;
    ANTENNADIFFAREA 0.434700 ;
    PORT
      LAYER met3 ;
        RECT 376.000 108.840 380.000 109.440 ;
    END
  END wr_buff_full
  PIN wr_buff_wdata[0]
    DIRECTION OUTPUT ;
    USE SIGNAL ;
    ANTENNADIFFAREA 0.340600 ;
    PORT
      LAYER met2 ;
        RECT 248.030 0.000 248.310 4.000 ;
    END
  END wr_buff_wdata[0]
  PIN wr_buff_wdata[1]
    DIRECTION OUTPUT ;
    USE SIGNAL ;
    ANTENNADIFFAREA 0.340600 ;
    PORT
      LAYER met2 ;
        RECT 238.370 0.000 238.650 4.000 ;
    END
  END wr_buff_wdata[1]
  PIN wr_buff_wdata[2]
    DIRECTION OUTPUT ;
    USE SIGNAL ;
    ANTENNADIFFAREA 0.340600 ;
    PORT
      LAYER met2 ;
        RECT 241.590 0.000 241.870 4.000 ;
    END
  END wr_buff_wdata[2]
  PIN wr_buff_wdata[3]
    DIRECTION OUTPUT ;
    USE SIGNAL ;
    ANTENNADIFFAREA 0.340600 ;
    PORT
      LAYER met2 ;
        RECT 273.790 0.000 274.070 4.000 ;
    END
  END wr_buff_wdata[3]
  PIN wr_buff_wdata[4]
    DIRECTION OUTPUT ;
    USE SIGNAL ;
    ANTENNADIFFAREA 0.340600 ;
    PORT
      LAYER met2 ;
        RECT 267.350 0.000 267.630 4.000 ;
    END
  END wr_buff_wdata[4]
  PIN wr_buff_wdata[5]
    DIRECTION OUTPUT ;
    USE SIGNAL ;
    ANTENNADIFFAREA 0.340600 ;
    PORT
      LAYER met2 ;
        RECT 244.810 0.000 245.090 4.000 ;
    END
  END wr_buff_wdata[5]
  PIN wr_buff_wdata[6]
    DIRECTION OUTPUT ;
    USE SIGNAL ;
    ANTENNADIFFAREA 0.340600 ;
    PORT
      LAYER met2 ;
        RECT 283.450 0.000 283.730 4.000 ;
    END
  END wr_buff_wdata[6]
  PIN wr_buff_wdata[7]
    DIRECTION OUTPUT ;
    USE SIGNAL ;
    ANTENNADIFFAREA 0.340600 ;
    PORT
      LAYER met2 ;
        RECT 264.130 0.000 264.410 4.000 ;
    END
  END wr_buff_wdata[7]
  PIN wr_buff_wren
    DIRECTION OUTPUT ;
    USE SIGNAL ;
    ANTENNADIFFAREA 0.340600 ;
    PORT
      LAYER met3 ;
        RECT 376.000 122.440 380.000 123.040 ;
    END
  END wr_buff_wren
  OBS
      LAYER nwell ;
        RECT 5.330 10.795 374.630 367.390 ;
      LAYER li1 ;
        RECT 5.520 10.795 374.440 367.285 ;
      LAYER met1 ;
        RECT 5.520 5.480 375.290 367.440 ;
      LAYER met2 ;
        RECT 21.070 4.280 375.270 367.385 ;
        RECT 21.070 3.670 22.350 4.280 ;
        RECT 23.190 3.670 25.570 4.280 ;
        RECT 26.410 3.670 28.790 4.280 ;
        RECT 29.630 3.670 32.010 4.280 ;
        RECT 32.850 3.670 35.230 4.280 ;
        RECT 36.070 3.670 38.450 4.280 ;
        RECT 39.290 3.670 41.670 4.280 ;
        RECT 42.510 3.670 44.890 4.280 ;
        RECT 45.730 3.670 48.110 4.280 ;
        RECT 48.950 3.670 51.330 4.280 ;
        RECT 52.170 3.670 54.550 4.280 ;
        RECT 55.390 3.670 57.770 4.280 ;
        RECT 58.610 3.670 60.990 4.280 ;
        RECT 61.830 3.670 64.210 4.280 ;
        RECT 65.050 3.670 67.430 4.280 ;
        RECT 68.270 3.670 70.650 4.280 ;
        RECT 71.490 3.670 73.870 4.280 ;
        RECT 74.710 3.670 221.990 4.280 ;
        RECT 222.830 3.670 225.210 4.280 ;
        RECT 226.050 3.670 228.430 4.280 ;
        RECT 229.270 3.670 231.650 4.280 ;
        RECT 232.490 3.670 234.870 4.280 ;
        RECT 235.710 3.670 238.090 4.280 ;
        RECT 238.930 3.670 241.310 4.280 ;
        RECT 242.150 3.670 244.530 4.280 ;
        RECT 245.370 3.670 247.750 4.280 ;
        RECT 248.590 3.670 250.970 4.280 ;
        RECT 251.810 3.670 254.190 4.280 ;
        RECT 255.030 3.670 257.410 4.280 ;
        RECT 258.250 3.670 260.630 4.280 ;
        RECT 261.470 3.670 263.850 4.280 ;
        RECT 264.690 3.670 267.070 4.280 ;
        RECT 267.910 3.670 270.290 4.280 ;
        RECT 271.130 3.670 273.510 4.280 ;
        RECT 274.350 3.670 276.730 4.280 ;
        RECT 277.570 3.670 279.950 4.280 ;
        RECT 280.790 3.670 283.170 4.280 ;
        RECT 284.010 3.670 286.390 4.280 ;
        RECT 287.230 3.670 289.610 4.280 ;
        RECT 290.450 3.670 292.830 4.280 ;
        RECT 293.670 3.670 296.050 4.280 ;
        RECT 296.890 3.670 299.270 4.280 ;
        RECT 300.110 3.670 302.490 4.280 ;
        RECT 303.330 3.670 305.710 4.280 ;
        RECT 306.550 3.670 308.930 4.280 ;
        RECT 309.770 3.670 312.150 4.280 ;
        RECT 312.990 3.670 315.370 4.280 ;
        RECT 316.210 3.670 318.590 4.280 ;
        RECT 319.430 3.670 321.810 4.280 ;
        RECT 322.650 3.670 375.270 4.280 ;
      LAYER met3 ;
        RECT 4.000 361.440 376.000 367.365 ;
        RECT 4.000 360.040 375.600 361.440 ;
        RECT 4.000 358.040 376.000 360.040 ;
        RECT 4.000 356.640 375.600 358.040 ;
        RECT 4.000 354.640 376.000 356.640 ;
        RECT 4.000 353.240 375.600 354.640 ;
        RECT 4.000 351.240 376.000 353.240 ;
        RECT 4.000 349.840 375.600 351.240 ;
        RECT 4.000 347.840 376.000 349.840 ;
        RECT 4.000 346.440 375.600 347.840 ;
        RECT 4.000 344.440 376.000 346.440 ;
        RECT 4.000 343.040 375.600 344.440 ;
        RECT 4.000 341.040 376.000 343.040 ;
        RECT 4.000 339.640 375.600 341.040 ;
        RECT 4.000 337.640 376.000 339.640 ;
        RECT 4.000 336.240 375.600 337.640 ;
        RECT 4.000 334.240 376.000 336.240 ;
        RECT 4.000 332.840 375.600 334.240 ;
        RECT 4.000 330.840 376.000 332.840 ;
        RECT 4.000 329.440 375.600 330.840 ;
        RECT 4.000 327.440 376.000 329.440 ;
        RECT 4.000 326.040 375.600 327.440 ;
        RECT 4.000 324.040 376.000 326.040 ;
        RECT 4.000 322.640 375.600 324.040 ;
        RECT 4.000 320.640 376.000 322.640 ;
        RECT 4.400 319.240 375.600 320.640 ;
        RECT 4.000 317.240 376.000 319.240 ;
        RECT 4.000 315.840 375.600 317.240 ;
        RECT 4.000 313.840 376.000 315.840 ;
        RECT 4.000 312.440 375.600 313.840 ;
        RECT 4.000 310.440 376.000 312.440 ;
        RECT 4.000 309.040 375.600 310.440 ;
        RECT 4.000 307.040 376.000 309.040 ;
        RECT 4.000 305.640 375.600 307.040 ;
        RECT 4.000 303.640 376.000 305.640 ;
        RECT 4.000 302.240 375.600 303.640 ;
        RECT 4.000 300.240 376.000 302.240 ;
        RECT 4.000 298.840 375.600 300.240 ;
        RECT 4.000 296.840 376.000 298.840 ;
        RECT 4.000 295.440 375.600 296.840 ;
        RECT 4.000 293.440 376.000 295.440 ;
        RECT 4.000 292.040 375.600 293.440 ;
        RECT 4.000 290.040 376.000 292.040 ;
        RECT 4.000 288.640 375.600 290.040 ;
        RECT 4.000 286.640 376.000 288.640 ;
        RECT 4.000 285.240 375.600 286.640 ;
        RECT 4.000 283.240 376.000 285.240 ;
        RECT 4.000 281.840 375.600 283.240 ;
        RECT 4.000 279.840 376.000 281.840 ;
        RECT 4.000 278.440 375.600 279.840 ;
        RECT 4.000 276.440 376.000 278.440 ;
        RECT 4.000 275.040 375.600 276.440 ;
        RECT 4.000 273.040 376.000 275.040 ;
        RECT 4.000 271.640 375.600 273.040 ;
        RECT 4.000 269.640 376.000 271.640 ;
        RECT 4.000 268.240 375.600 269.640 ;
        RECT 4.000 266.240 376.000 268.240 ;
        RECT 4.000 264.840 375.600 266.240 ;
        RECT 4.000 262.840 376.000 264.840 ;
        RECT 4.000 261.440 375.600 262.840 ;
        RECT 4.000 259.440 376.000 261.440 ;
        RECT 4.000 258.040 375.600 259.440 ;
        RECT 4.000 256.040 376.000 258.040 ;
        RECT 4.000 254.640 375.600 256.040 ;
        RECT 4.000 252.640 376.000 254.640 ;
        RECT 4.000 251.240 375.600 252.640 ;
        RECT 4.000 249.240 376.000 251.240 ;
        RECT 4.000 247.840 375.600 249.240 ;
        RECT 4.000 245.840 376.000 247.840 ;
        RECT 4.000 244.440 375.600 245.840 ;
        RECT 4.000 242.440 376.000 244.440 ;
        RECT 4.000 241.040 375.600 242.440 ;
        RECT 4.000 239.040 376.000 241.040 ;
        RECT 4.000 237.640 375.600 239.040 ;
        RECT 4.000 235.640 376.000 237.640 ;
        RECT 4.000 234.240 375.600 235.640 ;
        RECT 4.000 232.240 376.000 234.240 ;
        RECT 4.000 230.840 375.600 232.240 ;
        RECT 4.000 228.840 376.000 230.840 ;
        RECT 4.000 227.440 375.600 228.840 ;
        RECT 4.000 225.440 376.000 227.440 ;
        RECT 4.000 224.040 375.600 225.440 ;
        RECT 4.000 222.040 376.000 224.040 ;
        RECT 4.000 220.640 375.600 222.040 ;
        RECT 4.000 218.640 376.000 220.640 ;
        RECT 4.000 217.240 375.600 218.640 ;
        RECT 4.000 215.240 376.000 217.240 ;
        RECT 4.000 213.840 375.600 215.240 ;
        RECT 4.000 211.840 376.000 213.840 ;
        RECT 4.000 210.440 375.600 211.840 ;
        RECT 4.000 208.440 376.000 210.440 ;
        RECT 4.000 207.040 375.600 208.440 ;
        RECT 4.000 205.040 376.000 207.040 ;
        RECT 4.000 203.640 375.600 205.040 ;
        RECT 4.000 201.640 376.000 203.640 ;
        RECT 4.000 200.240 375.600 201.640 ;
        RECT 4.000 198.240 376.000 200.240 ;
        RECT 4.000 196.840 375.600 198.240 ;
        RECT 4.000 194.840 376.000 196.840 ;
        RECT 4.000 193.440 375.600 194.840 ;
        RECT 4.000 191.440 376.000 193.440 ;
        RECT 4.000 190.040 375.600 191.440 ;
        RECT 4.000 188.040 376.000 190.040 ;
        RECT 4.000 186.640 375.600 188.040 ;
        RECT 4.000 184.640 376.000 186.640 ;
        RECT 4.000 183.240 375.600 184.640 ;
        RECT 4.000 181.240 376.000 183.240 ;
        RECT 4.000 179.840 375.600 181.240 ;
        RECT 4.000 177.840 376.000 179.840 ;
        RECT 4.000 176.440 375.600 177.840 ;
        RECT 4.000 174.440 376.000 176.440 ;
        RECT 4.000 173.040 375.600 174.440 ;
        RECT 4.000 171.040 376.000 173.040 ;
        RECT 4.000 169.640 375.600 171.040 ;
        RECT 4.000 167.640 376.000 169.640 ;
        RECT 4.000 166.240 375.600 167.640 ;
        RECT 4.000 164.240 376.000 166.240 ;
        RECT 4.000 162.840 375.600 164.240 ;
        RECT 4.000 160.840 376.000 162.840 ;
        RECT 4.000 159.440 375.600 160.840 ;
        RECT 4.000 157.440 376.000 159.440 ;
        RECT 4.000 156.040 375.600 157.440 ;
        RECT 4.000 154.040 376.000 156.040 ;
        RECT 4.000 152.640 375.600 154.040 ;
        RECT 4.000 150.640 376.000 152.640 ;
        RECT 4.000 149.240 375.600 150.640 ;
        RECT 4.000 147.240 376.000 149.240 ;
        RECT 4.000 145.840 375.600 147.240 ;
        RECT 4.000 143.840 376.000 145.840 ;
        RECT 4.000 142.440 375.600 143.840 ;
        RECT 4.000 140.440 376.000 142.440 ;
        RECT 4.000 139.040 375.600 140.440 ;
        RECT 4.000 137.040 376.000 139.040 ;
        RECT 4.000 135.640 375.600 137.040 ;
        RECT 4.000 133.640 376.000 135.640 ;
        RECT 4.000 132.240 375.600 133.640 ;
        RECT 4.000 130.240 376.000 132.240 ;
        RECT 4.000 128.840 375.600 130.240 ;
        RECT 4.000 126.840 376.000 128.840 ;
        RECT 4.000 125.440 375.600 126.840 ;
        RECT 4.000 123.440 376.000 125.440 ;
        RECT 4.000 122.040 375.600 123.440 ;
        RECT 4.000 120.040 376.000 122.040 ;
        RECT 4.000 118.640 375.600 120.040 ;
        RECT 4.000 116.640 376.000 118.640 ;
        RECT 4.000 115.240 375.600 116.640 ;
        RECT 4.000 113.240 376.000 115.240 ;
        RECT 4.000 111.840 375.600 113.240 ;
        RECT 4.000 109.840 376.000 111.840 ;
        RECT 4.000 108.440 375.600 109.840 ;
        RECT 4.000 106.440 376.000 108.440 ;
        RECT 4.000 105.040 375.600 106.440 ;
        RECT 4.000 103.040 376.000 105.040 ;
        RECT 4.000 101.640 375.600 103.040 ;
        RECT 4.000 99.640 376.000 101.640 ;
        RECT 4.000 98.240 375.600 99.640 ;
        RECT 4.000 96.240 376.000 98.240 ;
        RECT 4.000 94.840 375.600 96.240 ;
        RECT 4.000 92.840 376.000 94.840 ;
        RECT 4.000 91.440 375.600 92.840 ;
        RECT 4.000 89.440 376.000 91.440 ;
        RECT 4.000 88.040 375.600 89.440 ;
        RECT 4.000 86.040 376.000 88.040 ;
        RECT 4.000 84.640 375.600 86.040 ;
        RECT 4.000 82.640 376.000 84.640 ;
        RECT 4.000 81.240 375.600 82.640 ;
        RECT 4.000 79.240 376.000 81.240 ;
        RECT 4.000 77.840 375.600 79.240 ;
        RECT 4.000 75.840 376.000 77.840 ;
        RECT 4.000 74.440 375.600 75.840 ;
        RECT 4.000 72.440 376.000 74.440 ;
        RECT 4.000 71.040 375.600 72.440 ;
        RECT 4.000 69.040 376.000 71.040 ;
        RECT 4.000 67.640 375.600 69.040 ;
        RECT 4.000 65.640 376.000 67.640 ;
        RECT 4.000 64.240 375.600 65.640 ;
        RECT 4.000 62.240 376.000 64.240 ;
        RECT 4.000 60.840 375.600 62.240 ;
        RECT 4.000 58.840 376.000 60.840 ;
        RECT 4.000 57.440 375.600 58.840 ;
        RECT 4.000 55.440 376.000 57.440 ;
        RECT 4.000 54.040 375.600 55.440 ;
        RECT 4.000 52.040 376.000 54.040 ;
        RECT 4.000 50.640 375.600 52.040 ;
        RECT 4.000 48.640 376.000 50.640 ;
        RECT 4.000 47.240 375.600 48.640 ;
        RECT 4.000 45.240 376.000 47.240 ;
        RECT 4.000 43.840 375.600 45.240 ;
        RECT 4.000 41.840 376.000 43.840 ;
        RECT 4.000 40.440 375.600 41.840 ;
        RECT 4.000 38.440 376.000 40.440 ;
        RECT 4.000 37.040 375.600 38.440 ;
        RECT 4.000 35.040 376.000 37.040 ;
        RECT 4.000 33.640 375.600 35.040 ;
        RECT 4.000 31.640 376.000 33.640 ;
        RECT 4.000 30.240 375.600 31.640 ;
        RECT 4.000 28.240 376.000 30.240 ;
        RECT 4.000 26.840 375.600 28.240 ;
        RECT 4.000 24.840 376.000 26.840 ;
        RECT 4.000 23.440 375.600 24.840 ;
        RECT 4.000 21.440 376.000 23.440 ;
        RECT 4.000 20.040 375.600 21.440 ;
        RECT 4.000 10.715 376.000 20.040 ;
      LAYER met4 ;
        RECT 336.095 26.695 370.465 356.825 ;
  END
END mask_generator
END LIBRARY

